VERSION 5.8 ;
BUSBITCHARS "[]" ;
DIVIDERCHAR "/" ;
UNITS
    DATABASE MICRONS 1000 ;
END UNITS

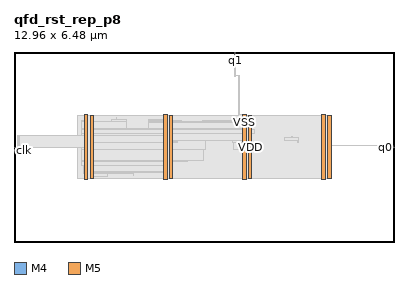
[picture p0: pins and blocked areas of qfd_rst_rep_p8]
MACRO qfd_rst_rep_p8
  FOREIGN qfd_rst_rep_p8 0 0 ;
  CLASS BLOCK ;
  SIZE 12.96 BY 6.48 ;
  PIN clk
    DIRECTION INPUT ;
    USE SIGNAL ;
    PORT
      LAYER M4 ;
        RECT  0 3.12 0.084 3.144 ;
    END
  END clk
  PIN d
    DIRECTION INPUT ;
    USE SIGNAL ;
    PORT
      LAYER M4 ;
        RECT  0 3.216 0.084 3.24 ;
    END
  END d
  PIN q0
    DIRECTION OUTPUT ;
    USE SIGNAL ;
    PORT
      LAYER M4 ;
        RECT  12.876 3.216 12.96 3.24 ;
    END
  END q0
  PIN q1
    DIRECTION OUTPUT ;
    USE SIGNAL ;
    PORT
      LAYER M5 ;
        RECT  7.536 6.396 7.56 6.48 ;
    END
  END q1
  PIN VSS
    DIRECTION INOUT ;
    USE GROUND ;
    PORT
      LAYER M5 ;
        RECT  10.5 2.137 10.62 4.343 ;
        RECT  7.8 2.137 7.92 4.343 ;
        RECT  5.1 2.137 5.22 4.343 ;
        RECT  2.4 2.137 2.52 4.343 ;
    END
  END VSS
  PIN VDD
    DIRECTION INOUT ;
    USE POWER ;
    PORT
      LAYER M5 ;
        RECT  10.692 2.151 10.812 4.329 ;
        RECT  7.992 2.151 8.112 4.329 ;
        RECT  5.292 2.151 5.412 4.329 ;
        RECT  2.592 2.151 2.712 4.329 ;
    END
  END VDD
  OBS
    LAYER RVTN ;
     RECT  2.16 2.16 10.8 2.295 ;
     RECT  2.16 2.565 10.8 2.835 ;
     RECT  2.16 3.105 10.8 3.375 ;
     RECT  2.16 3.645 10.8 3.915 ;
     RECT  2.16 4.185 10.8 4.32 ;
    LAYER RVTP ;
     RECT  2.16 2.295 10.8 2.565 ;
     RECT  2.16 2.835 10.8 3.105 ;
     RECT  2.16 3.375 10.8 3.645 ;
     RECT  2.16 3.915 10.8 4.185 ;
    LAYER M1 ;
     RECT  2.16 2.151 10.8 4.329 ;
    LAYER M2 ;
     RECT  2.16 2.151 10.8 4.329 ;
     RECT  10.8 2.421 10.812 4.059 ;
     RECT  10.812 3.276 12.875 3.294 ;
    LAYER M3 ;
     RECT  2.415 2.143 2.505 2.227 ;
     RECT  2.415 2.227 3.186 2.335 ;
     RECT  4.068 2.263 4.086 2.335 ;
     RECT  2.376 2.335 4.086 2.371 ;
     RECT  5.115 2.143 5.205 2.371 ;
     RECT  2.376 2.371 5.205 2.413 ;
     RECT  7.815 2.143 7.905 2.413 ;
     RECT  10.515 2.143 10.605 2.413 ;
     RECT  2.376 2.413 5.397 2.605 ;
     RECT  2.304 2.605 5.397 2.731 ;
     RECT  2.304 2.731 5.922 2.767 ;
     RECT  2.304 2.767 6.462 3.145 ;
     RECT  7.815 2.413 8.097 3.145 ;
     RECT  12.852 3.211 12.87 3.299 ;
     RECT  7.488 3.145 8.097 3.379 ;
     RECT  2.304 3.145 6.534 3.451 ;
     RECT  7.452 3.379 8.097 3.451 ;
     RECT  9.684 3.379 9.702 3.451 ;
     RECT  9.216 3.451 9.702 3.569 ;
     RECT  9.468 3.569 9.486 3.605 ;
     RECT  2.304 3.451 8.097 3.685 ;
     RECT  2.304 3.685 8.19 3.839 ;
     RECT  2.304 3.839 8.097 3.875 ;
     RECT  4.572 3.875 8.097 4.067 ;
     RECT  10.515 2.413 10.797 4.067 ;
     RECT  2.304 3.875 3.834 4.109 ;
     RECT  4.572 4.067 7.905 4.109 ;
     RECT  2.304 4.109 2.505 4.145 ;
     RECT  4.572 4.109 5.706 4.145 ;
     RECT  6.444 4.109 7.905 4.145 ;
     RECT  3.312 4.109 3.834 4.181 ;
     RECT  4.572 4.145 5.205 4.181 ;
     RECT  3.492 4.181 3.51 4.253 ;
     RECT  2.415 4.145 2.505 4.337 ;
     RECT  5.115 4.181 5.205 4.337 ;
     RECT  7.668 4.145 7.905 4.337 ;
     RECT  10.515 4.067 10.605 4.337 ;
     RECT  7.668 4.337 7.686 5.693 ;
    LAYER M4 ;
     RECT  0.06 3.12 0.133 3.24 ;
     RECT  0.133 3.12 0.179 3.624 ;
     RECT  0.179 3.216 2.401 3.624 ;
     RECT  2.401 2.352 2.408 3.624 ;
     RECT  2.408 2.148 2.512 4.332 ;
     RECT  2.512 2.352 2.704 4.062 ;
     RECT  2.704 2.352 3.521 2.376 ;
     RECT  2.704 3.408 5.108 3.624 ;
     RECT  5.108 2.148 5.212 4.332 ;
     RECT  5.212 2.418 5.404 4.062 ;
     RECT  5.404 3.408 5.573 3.432 ;
     RECT  7.525 5.664 7.697 5.688 ;
     RECT  7.808 2.148 7.912 4.332 ;
     RECT  7.912 2.418 8.104 4.062 ;
     RECT  10.508 2.148 10.612 4.332 ;
     RECT  10.612 2.418 10.804 4.062 ;
     RECT  12.841 3.216 12.924 3.24 ;
    LAYER M5 ;
     RECT  2.4 2.137 2.52 2.151 ;
     RECT  5.1 2.137 5.22 2.151 ;
     RECT  7.8 2.137 7.92 2.151 ;
     RECT  10.5 2.137 10.62 2.151 ;
     RECT  0.144 3.109 0.168 3.635 ;
     RECT  2.4 2.151 2.712 4.329 ;
     RECT  5.1 2.151 5.412 4.329 ;
     RECT  7.8 2.151 8.112 4.329 ;
     RECT  10.5 2.151 10.812 4.329 ;
     RECT  2.4 4.329 2.52 4.343 ;
     RECT  5.1 4.329 5.22 4.343 ;
     RECT  7.8 4.329 7.92 4.343 ;
     RECT  10.5 4.329 10.62 4.343 ;
     RECT  7.536 5.653 7.56 6.416 ;
  END
END qfd_rst_rep_p8
END LIBRARY
